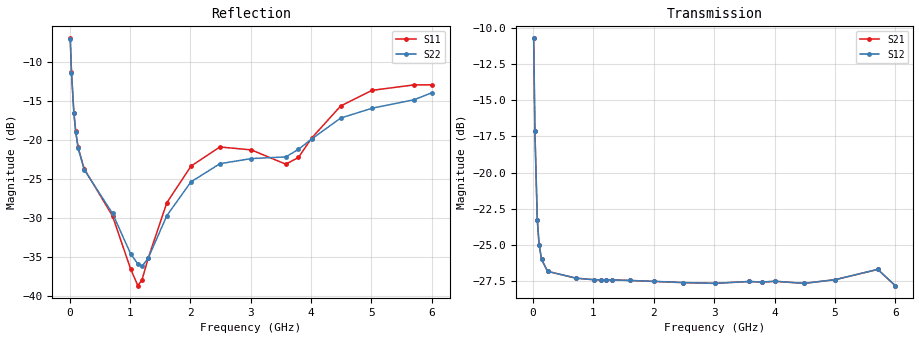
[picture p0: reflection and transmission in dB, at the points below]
! Integrated Device Technology
! Corporate Headquarters
! 6024 Silver Creek Valley Road
! San Jose, CA 95138  USA
! Phone:  1-408-284-8200
! Toll Free:  1-800-223-1366
! Webpage:  http://www.idt.com/
! Timing and RF Division
! 515 Groton Road, Suite 102
! Westford, MA 01886-6024
! Device:  F1951
! Description: 6-bit 0.5 dB Digital Step Attenuator
! Frequency:  100.0 -  4000.00 MHz
! Package:  4x4 mm Thin QFN Plastic Package: 24 pin
! Ports:  2 RF, 6 DC
!  Pin  1  = NC
!  Pin  2  = RF1  =  Port 1
!  Pin  3  = GND
!  Pin  4  = NC
!  Pin  5  = Serial Data Out (SDO)
!  Pin  6  = NC
!  Pin  7  = Reset Bar ( RSTb)
!  Pin  8  = Clock (CLK)
!  Pin  9  = Chip Select Bar (CSb)
!  Pin 10  = NC
!  Pin 11  = Serial Data In (SDI)
!  Pin 12  = NC
!  Pin 13  = NC
!  Pin 14  = VDD
!  Pin 15  = NC
!  Pin 16  = GND
!  Pin 17  = RF2  =  Port 2
!  Pin 18  = NC
!  Pin 19  = GND
!  Pin 20  = GND
!  Pin 21  = GND
!  Pin 22  = GND
!  Pin 23  = GND
!  Pin 24  = GND
! State:  53
! Atten State:  26.5 dB
! Voltage:  +3.30 Volts
! Current:  0.489 mA
! Data:  The device was measured on a F195X evaluation board which has
!  individual transmission lines to the RF pins.  Data was collected
!  de-embedded using a Automatic Fixture Removal [AFR] (Keysight Technologies).
!  The reference plane is the edge of the package pin.
! Misc:  Lot Code  1225BCA
!  Action Tracker AT0399
! Date Measured:  2018-09-13
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# GHz S dB R 50
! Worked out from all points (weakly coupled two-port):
!   600 points, 10 MHz to 6 GHz, reference 50 ohm
!   highest |S21| = -10.74 dB at 10 MHz (marker M1); lowest = -27.8 dB at 6 GHz (marker M2)
!   lowest |S11| = -38.7 dB at 1.13 GHz (marker M3), VSWR 1.02, Z = 48.9 + j0.157 ohm
!   |S11| at or under -10 dB: 23.32 MHz to end of sweep
!   |S22| runs from -36.3 to -7.1 dB; largest |S21 - S12| = 0.00015
!   S11 on the Smith chart (normalised r, x): 10 MHz: 1.77, -1.09; 30 MHz: 1.13, -0.59; 70 MHz: 0.97, -0.30; 1.3 GHz: 0.98, +0.03; 6 GHz: 0.80, +0.37
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0.01  -6.96 -33.4  -10.74 -37.3  -10.74 -37.3  -7.06 -33.3
0.03  -11.30 -61.7  -17.16 -56.5  -17.16 -56.5  -11.37 -61.6
0.07  -16.50 -86.8  -23.28 -47.7  -23.28 -47.7  -16.59 -86.9
0.1  -18.90 -97.6  -24.98 -38.8  -24.98 -38.8  -18.95 -97.8
0.14  -20.97 -108.0  -25.99 -30.8  -25.99 -30.8  -21.04 -107.7
0.24  -23.69 -122.4  -26.82 -21.0  -26.82 -21.0  -23.81 -122.5
0.71  -29.76 -135.2  -27.29 -14.9  -27.29 -15.0  -29.43 -138.3
1.01  -36.57 -155.3  -27.40 -16.6  -27.40 -16.6  -34.62 -152.6
1.13  -38.71 172.1  -27.41 -17.3  -27.41 -17.3  -35.91 -169.7
1.2  -37.93 149.2  -27.41 -17.9  -27.41 -17.9  -36.21 175.9
1.3  -35.20 128.3  -27.41 -18.8  -27.41 -18.7  -35.19 157.3
1.61  -28.06 115.8  -27.45 -21.7  -27.45 -21.7  -29.72 134.4
2.01  -23.36 123.6  -27.52 -25.9  -27.51 -25.9  -25.38 135.3
2.49  -20.90 136.5  -27.60 -30.8  -27.59 -30.8  -23.05 142.4
3.01  -21.28 146.6  -27.65 -35.9  -27.65 -35.9  -22.39 145.8
3.58  -23.11 125.7  -27.52 -41.4  -27.52 -41.5  -22.18 128.8
3.79  -22.25 109.9  -27.56 -43.6  -27.56 -43.6  -21.21 122.0
4.01  -19.75 101.3  -27.51 -45.8  -27.50 -45.8  -19.87 116.6
4.49  -15.64 99.4  -27.65 -50.1  -27.65 -50.1  -17.19 114.7
5.01  -13.63 108.2  -27.39 -52.7  -27.39 -52.7  -15.93 117.0
5.71  -12.93 113.0  -26.69 -64.2  -26.68 -64.2  -14.83 109.8
6  -12.93 106.8  -27.81 -66.3  -27.80 -66.3  -13.94 106.0
